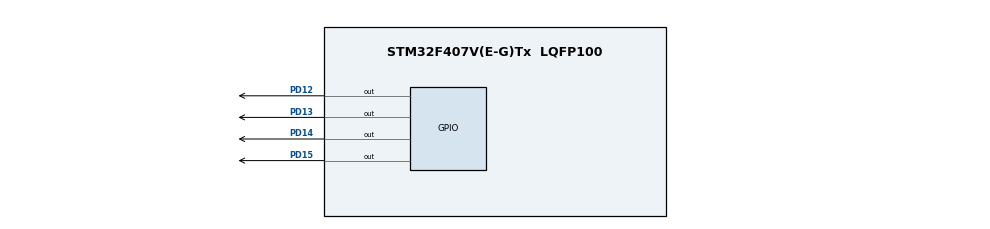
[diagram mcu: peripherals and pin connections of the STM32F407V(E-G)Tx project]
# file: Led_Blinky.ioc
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Mcu.Family=STM32F4
Mcu.Name=STM32F407V(E-G)Tx
Mcu.Package=LQFP100
NVIC.PriorityGroup=NVIC_PRIORITYGROUP_4
NVIC.RCC_IRQn=true\:0\:0\:false\:false\:true\:true
PA13.Mode=Serial_Wire
PA13.Signal=SYS_JTMS-SWDIO
PA14.Mode=Serial_Wire
PA14.Signal=SYS_JTCK-SWCLK
PD12.Signal=GPIO_Output
PD13.Signal=GPIO_Output
PD14.Signal=GPIO_Output
PD15.Signal=GPIO_Output
PH0-OSC_IN.Mode=HSE-External-Oscillator
PH0-OSC_IN.Signal=RCC_OSC_IN
PH1-OSC_OUT.Mode=HSE-External-Oscillator
PH1-OSC_OUT.Signal=RCC_OSC_OUT
ProjectManager.HeapSize=0x200
ProjectManager.StackSize=0x400
ProjectManager.TargetToolchain=MDK-ARM V5
RCC.48MHZClocksFreq_Value=84000000
RCC.AHBFreq_Value=168000000
RCC.APB1CLKDivider=RCC_HCLK_DIV4
RCC.APB1Freq_Value=42000000
RCC.APB1TimFreq_Value=84000000
RCC.APB2CLKDivider=RCC_HCLK_DIV2
RCC.APB2Freq_Value=84000000
RCC.APB2TimFreq_Value=168000000
RCC.CortexFreq_Value=168000000
RCC.HCLKFreq_Value=168000000
RCC.HSE_VALUE=25000000
RCC.HSI_VALUE=16000000
RCC.LSE_VALUE=32768
RCC.PLLM=8
RCC.PLLN=168
RCC.SYSCLKFreq_VALUE=168000000
RCC.SYSCLKSource=RCC_SYSCLKSOURCE_PLLCLK
RCC.VCOOutputFreq_Value=336000000
board=custom

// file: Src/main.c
/**
  ******************************************************************************
  * @file           : main.c
  * @brief          : Main program body
  ******************************************************************************
  ** This notice applies to any and all portions of this file
  * that are not between comment pairs USER CODE BEGIN and
  * USER CODE END. Other portions of this file, whether
  * inserted by the user or by software development tools
  * are owned by their respective copyright owners.
  *
  * COPYRIGHT(c) 2019 STMicroelectronics
  *
  * Redistribution and use in source and binary forms, with or without modification,
  * are permitted provided that the following conditions are met:
  *   1. Redistributions of source code must retain the above copyright notice,
  *      this list of conditions and the following disclaimer.
  *   2. Redistributions in binary form must reproduce the above copyright notice,
  *      this list of conditions and the following disclaimer in the documentation
  *      and/or other materials provided with the distribution.
  *   3. Neither the name of STMicroelectronics nor the names of its contributors
  *      may be used to endorse or promote products derived from this software
  *      without specific prior written permission.
  *
  * THIS SOFTWARE IS PROVIDED BY THE COPYRIGHT HOLDERS AND CONTRIBUTORS "AS IS"
  * AND ANY EXPRESS OR IMPLIED WARRANTIES, INCLUDING, BUT NOT LIMITED TO, THE
  * IMPLIED WARRANTIES OF MERCHANTABILITY AND FITNESS FOR A PARTICULAR PURPOSE ARE
  * DISCLAIMED. IN NO EVENT SHALL THE COPYRIGHT HOLDER OR CONTRIBUTORS BE LIABLE
  * FOR ANY DIRECT, INDIRECT, INCIDENTAL, SPECIAL, EXEMPLARY, OR CONSEQUENTIAL
  * DAMAGES (INCLUDING, BUT NOT LIMITED TO, PROCUREMENT OF SUBSTITUTE GOODS OR
  * SERVICES; LOSS OF USE, DATA, OR PROFITS; OR BUSINESS INTERRUPTION) HOWEVER
  * CAUSED AND ON ANY THEORY OF LIABILITY, WHETHER IN CONTRACT, STRICT LIABILITY,
  * OR TORT (INCLUDING NEGLIGENCE OR OTHERWISE) ARISING IN ANY WAY OUT OF THE USE
  * OF THIS SOFTWARE, EVEN IF ADVISED OF THE POSSIBILITY OF SUCH DAMAGE.
  *
  ******************************************************************************
  */
#include "main.h"
#include "stm32f4xx_hal.h"

/* USER CODE BEGIN PV */
/* Private variables ---------------------------------------------------------*/

/* USER CODE END PV */

void SystemClock_Config(void);
static void MX_GPIO_Init(void);

/* USER CODE BEGIN PFP */
/* Private function prototypes -----------------------------------------------*/

/* USER CODE END PFP */

int main(void)
{

  /* MCU Configuration----------------------------------------------------------*/

  /* Reset of all peripherals, Initializes the Flash interface and the Systick. */
  HAL_Init();

  /* Configure the system clock */
  SystemClock_Config();

  /* Initialize all configured peripherals */
  MX_GPIO_Init();

  /* Infinite loop */
  while (1)
  {

  /* USER CODE BEGIN 3 */
		HAL_GPIO_TogglePin(GPIOD, GPIO_PIN_15);
		HAL_Delay(100);
		HAL_GPIO_TogglePin(GPIOD, GPIO_PIN_14);
		HAL_Delay(100);
		HAL_GPIO_TogglePin(GPIOD, GPIO_PIN_13);
		HAL_Delay(100);
		HAL_GPIO_TogglePin(GPIOD, GPIO_PIN_12);
		HAL_Delay(100);

  }
  /* USER CODE END 3 */

}

void SystemClock_Config(void)
{

  RCC_OscInitTypeDef RCC_OscInitStruct;
  RCC_ClkInitTypeDef RCC_ClkInitStruct;

    /**Configure the main internal regulator output voltage
    */
  __HAL_RCC_PWR_CLK_ENABLE();

  __HAL_PWR_VOLTAGESCALING_CONFIG(PWR_REGULATOR_VOLTAGE_SCALE1);

    /**Initializes the CPU, AHB and APB busses clocks
    */
  RCC_OscInitStruct.OscillatorType = RCC_OSCILLATORTYPE_HSE;
  RCC_OscInitStruct.HSEState = RCC_HSE_ON;
  RCC_OscInitStruct.PLL.PLLState = RCC_PLL_ON;
  RCC_OscInitStruct.PLL.PLLSource = RCC_PLLSOURCE_HSE;
  RCC_OscInitStruct.PLL.PLLM = 8;
  RCC_OscInitStruct.PLL.PLLN = 336;
  RCC_OscInitStruct.PLL.PLLP = RCC_PLLP_DIV2;
  RCC_OscInitStruct.PLL.PLLQ = 7;
  if (HAL_RCC_OscConfig(&RCC_OscInitStruct) != HAL_OK)
  {
    _Error_Handler(__FILE__, __LINE__);
  }

    /**Initializes the CPU, AHB and APB busses clocks
    */
  RCC_ClkInitStruct.ClockType = RCC_CLOCKTYPE_HCLK|RCC_CLOCKTYPE_SYSCLK
                              |RCC_CLOCKTYPE_PCLK1|RCC_CLOCKTYPE_PCLK2;
  RCC_ClkInitStruct.SYSCLKSource = RCC_SYSCLKSOURCE_PLLCLK;
  RCC_ClkInitStruct.AHBCLKDivider = RCC_SYSCLK_DIV1;
  RCC_ClkInitStruct.APB1CLKDivider = RCC_HCLK_DIV4;
  RCC_ClkInitStruct.APB2CLKDivider = RCC_HCLK_DIV2;

  if (HAL_RCC_ClockConfig(&RCC_ClkInitStruct, FLASH_LATENCY_5) != HAL_OK)
  {
    _Error_Handler(__FILE__, __LINE__);
  }

    /**Configure the Systick interrupt time
    */
  HAL_SYSTICK_Config(HAL_RCC_GetHCLKFreq()/1000);

    /**Configure the Systick
    */
  HAL_SYSTICK_CLKSourceConfig(SYSTICK_CLKSOURCE_HCLK);

  /* SysTick_IRQn interrupt configuration */
  HAL_NVIC_SetPriority(SysTick_IRQn, 0, 0);
}

/** Configure pins as
        * Analog
        * Input
        * Output
        * EVENT_OUT
        * EXTI
*/
static void MX_GPIO_Init(void)
{

  GPIO_InitTypeDef GPIO_InitStruct;

  /* GPIO Ports Clock Enable */
  __HAL_RCC_GPIOH_CLK_ENABLE();
  __HAL_RCC_GPIOD_CLK_ENABLE();
  __HAL_RCC_GPIOA_CLK_ENABLE();

  /*Configure GPIO pin Output Level */
  HAL_GPIO_WritePin(GPIOD, GPIO_PIN_12|GPIO_PIN_13|GPIO_PIN_14|GPIO_PIN_15, GPIO_PIN_RESET);

  /*Configure GPIO pins : PD12 PD13 PD14 PD15 */
  GPIO_InitStruct.Pin = GPIO_PIN_12|GPIO_PIN_13|GPIO_PIN_14|GPIO_PIN_15;
  GPIO_InitStruct.Mode = GPIO_MODE_OUTPUT_PP;
  GPIO_InitStruct.Pull = GPIO_NOPULL;
  GPIO_InitStruct.Speed = GPIO_SPEED_FREQ_LOW;
  HAL_GPIO_Init(GPIOD, &GPIO_InitStruct);

}

void _Error_Handler(char *file, int line)
{
  while(1)
  {
  }
}

/************************ (C) COPYRIGHT STMicroelectronics *****END OF FILE****/
